VERSION 5.7 ;
  NOWIREEXTENSIONATPIN ON ;
  DIVIDERCHAR "/" ;
  BUSBITCHARS "[]" ;
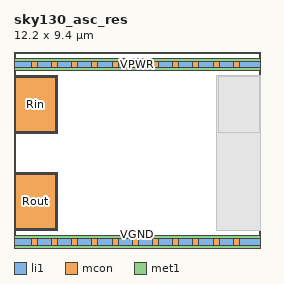
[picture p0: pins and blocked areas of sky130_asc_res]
MACRO sky130_asc_res
  CLASS CORE ;
  FOREIGN sky130_asc_res ;
  ORIGIN 0.000 0.000 ;
  SIZE 12.200 BY 9.400 ;
  SITE unitasc ;
  PIN Rin
    DIRECTION INOUT ;
    PORT
      LAYER li1 ;
        RECT 0.000 5.375 2.160 8.225 ;
      LAYER mcon ;
        RECT 0.090 5.455 2.075 8.145 ;
      LAYER met1 ;
        RECT 0.055 5.395 2.105 8.205 ;
    END
  END Rin
  PIN Rout
    DIRECTION INOUT ;
    PORT
      LAYER li1 ;
        RECT 0.000 0.575 2.160 3.425 ;
      LAYER mcon ;
        RECT 0.090 0.655 2.075 3.345 ;
      LAYER met1 ;
        RECT 0.055 0.595 2.105 3.405 ;
    END
  END Rout
  PIN VPWR
    DIRECTION INOUT ;
    USE POWER ;
    PORT
      LAYER li1 ;
        RECT 0.000 8.650 12.200 8.950 ;
      LAYER mcon ;
        RECT 0.850 8.650 1.150 8.950 ;
        RECT 1.850 8.650 2.150 8.950 ;
        RECT 2.850 8.650 3.150 8.950 ;
        RECT 3.850 8.650 4.150 8.950 ;
        RECT 4.850 8.650 5.150 8.950 ;
        RECT 5.850 8.650 6.150 8.950 ;
        RECT 6.850 8.650 7.150 8.950 ;
        RECT 7.850 8.650 8.150 8.950 ;
        RECT 8.850 8.650 9.150 8.950 ;
        RECT 9.850 8.650 10.150 8.950 ;
        RECT 10.850 8.650 11.150 8.950 ;
      LAYER met1 ;
        RECT 0.000 8.500 12.200 9.100 ;
    END
  END VPWR
  PIN VGND
    DIRECTION INOUT ;
    USE GROUND ;
    PORT
      LAYER li1 ;
        RECT 0.000 -0.150 12.200 0.150 ;
      LAYER mcon ;
        RECT 0.850 -0.150 1.150 0.150 ;
        RECT 1.850 -0.150 2.150 0.150 ;
        RECT 2.850 -0.150 3.150 0.150 ;
        RECT 3.850 -0.150 4.150 0.150 ;
        RECT 4.850 -0.150 5.150 0.150 ;
        RECT 5.850 -0.150 6.150 0.150 ;
        RECT 6.850 -0.150 7.150 0.150 ;
        RECT 7.850 -0.150 8.150 0.150 ;
        RECT 8.850 -0.150 9.150 0.150 ;
        RECT 9.850 -0.150 10.150 0.150 ;
        RECT 10.850 -0.150 11.150 0.150 ;
      LAYER met1 ;
        RECT 0.000 -0.300 12.200 0.300 ;
    END
  END VGND
  OBS
      LAYER li1 ;
        RECT 10.040 0.575 12.200 8.225 ;
      LAYER mcon ;
        RECT 10.125 5.455 12.110 8.145 ;
        RECT 10.125 0.655 12.110 3.345 ;
      LAYER met1 ;
        RECT 10.095 5.395 12.145 8.205 ;
        RECT 10.040 0.575 12.200 5.395 ;
  END
END sky130_asc_res
END LIBRARY

